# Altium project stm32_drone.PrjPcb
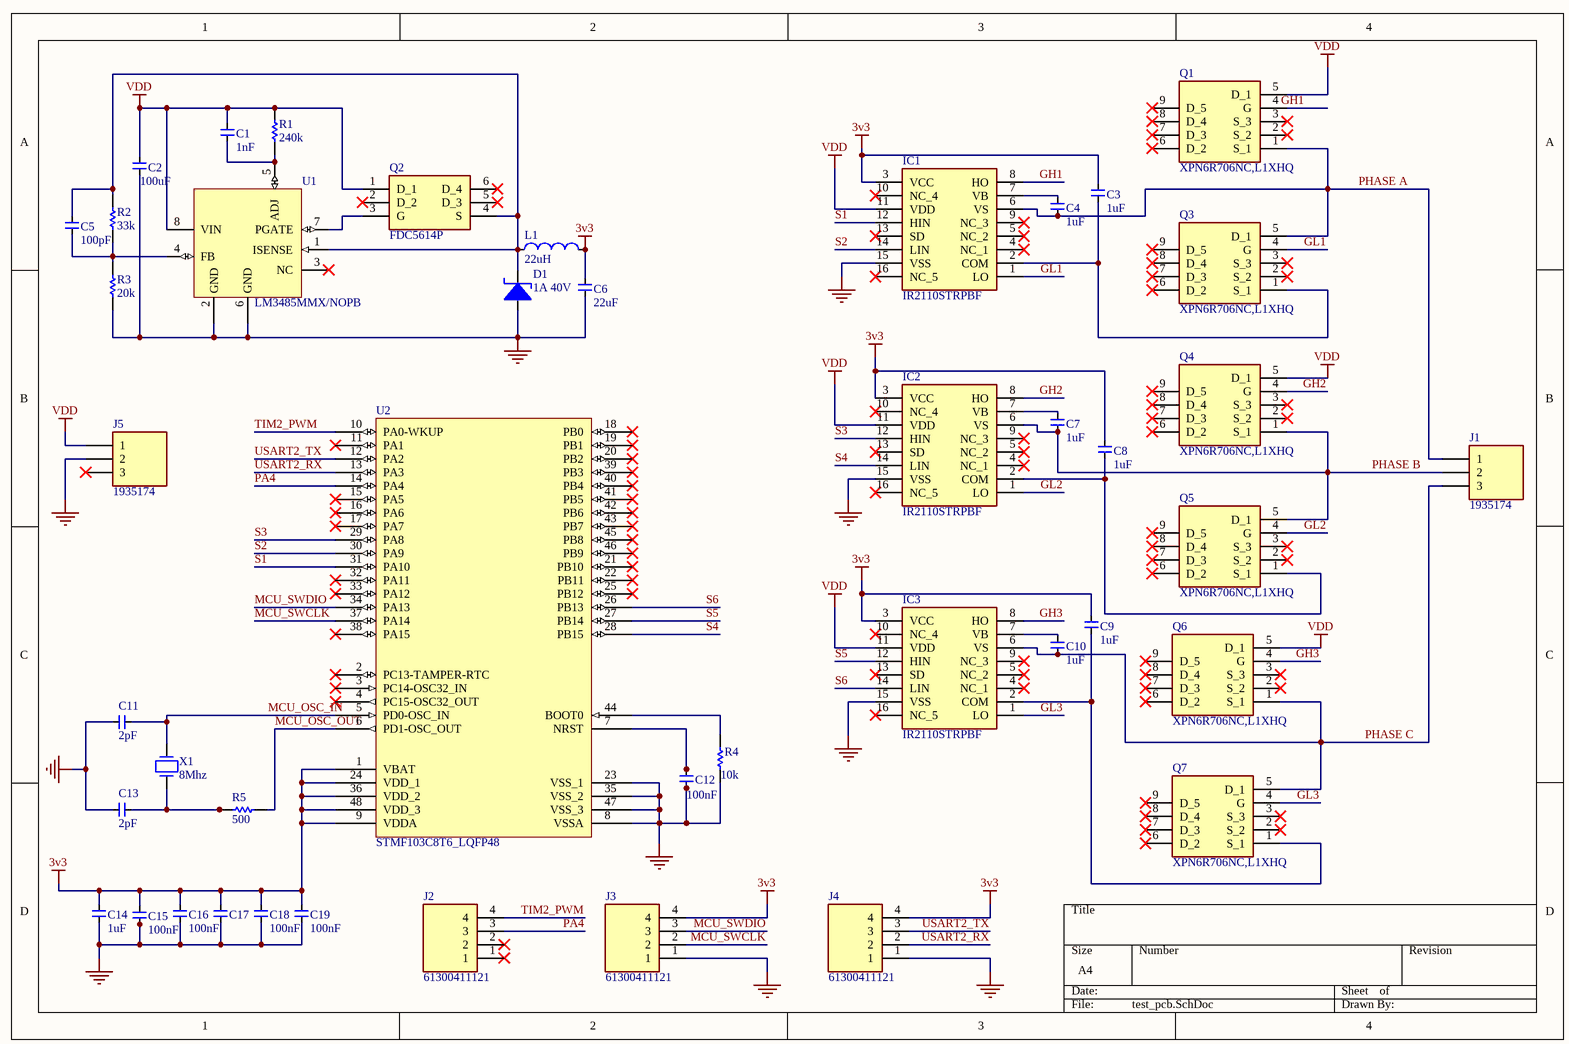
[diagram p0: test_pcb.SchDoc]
1 sheet, 44 parts. Net scope: global (net labels, ports and power ports of the same name join across sheets).
Board file: stm32_drone.PcbDoc

## Sheet test_pcb.SchDoc
size A4; SheetNumber: 1; SheetTotal: 1

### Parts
C1  1nF  [C0402C104J4RACTU]
C2  100uF  [GRM31x]
C3  1uF  [CAPC1608X90N]
C4  1uF  [GRM033D70J224ME01D]
C5  100pF  [CAPC0603X33N]
C6  22uF  [CAPC2012X145N]
C7  1uF  [GRM033D70J224ME01D]
C8  1uF  [GRM033D70J224ME01D]
C9  1uF  [GRM033D70J224ME01D]
C10  1uF  [GRM033D70J224ME01D]
C11  2pF  [GJM033]
C12  100nF  [GRM033D70J224ME01D]
C13  2pF  [GJM033]
C14  1uF  [CAPC1608X90N]
C15  100nF  [GRM033D70J224ME01D]
C16  100nF  [GRM033D70J224ME01D]
C17  (no value)  [GRM033D70J224ME01D]
C18  100nF  [GRM033D70J224ME01D]
C19  100nF  [GRM033D70J224ME01D]
D1  1A 40V  [DIOM5026X262N]
IC1  IR2110STRPBF  [SOIC127P1032X265-16N]
IC2  IR2110STRPBF  [SOIC127P1032X265-16N]
IC3  IR2110STRPBF  [SOIC127P1032X265-16N]
J1  1935174  [1935174]
J2  61300411121  [HDRV4W95P0X254_1X4_1016X254X854P]
J3  61300411121  [HDRV4W95P0X254_1X4_1016X254X854P]
J4  61300411121  [HDRV4W95P0X254_1X4_1016X254X854P]
J5  1935174  [1935174]
L1  22uH  [INDPM7166X300N]
Q1  XPN6R706NC,L1XHQ  [XPN6R706NCL1XHQ]
Q2  FDC5614P  [SOT95P280X110-6N]
Q3  XPN6R706NC,L1XHQ  [XPN6R706NCL1XHQ]
Q4  XPN6R706NC,L1XHQ  [XPN6R706NCL1XHQ]
Q5  XPN6R706NC,L1XHQ  [XPN6R706NCL1XHQ]
Q6  XPN6R706NC,L1XHQ  [XPN6R706NCL1XHQ]
Q7  XPN6R706NC,L1XHQ  [XPN6R706NCL1XHQ]
R1  240k  [ERJ3EKF1000V]
R2  33k  [ERA3AEB101V]
R3  20k  [ERJ2RKD1004X]
R4  10k  [RESC3115X60N]
R5  500  [ERA2AED122X]
U1  LM3485MMX/NOPB  [SOP65P490X110-8N]
U2  STMF103C8T6_LQFP48  [STM32F103C8T6_LQFP48]
X1  8Mhz  [8Mhz Crystal]

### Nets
3v3: C3.2 C6.2 C8.2 C9.2 C14.2 C15.2 C16.2 C17.2 C18.2 C19.2 IC1.3(VCC) IC2.3(VCC) IC3.3(VCC) J3.4 J4.4 L1.2 U2.1(VBAT) U2.9(VDDA) U2.24(VDD_1) U2.36(VDD_2) U2.48(VDD_3)
GND: C2.1 C6.1 C11.1 C12.1 C13.1 C14.1 C15.1 C16.1 C17.1 C18.1 C19.1 D1.+ IC1.15(VSS) IC2.15(VSS) IC3.15(VSS) J3.1 J4.1 J5.2 R3.4 R4.4 U1.2(GND) U1.6(GND) U2.8(VSSA) U2.23(VSS_1) U2.35(VSS_2) U2.47(VSS_3)
VDD: C1.2 C2.2 IC1.11(VDD) IC2.11(VDD) IC3.11(VDD) J5.1 Q1.5(D_1) Q2.1(D_1) Q4.5(D_1) Q6.5(D_1) R1.2 U1.8(VIN)
GH1: IC1.8(HO) Q1.4(G)
GH2: IC2.8(HO) Q4.4(G)
GH3: IC3.8(HO) Q6.4(G)
GL1: IC1.1(LO) Q3.4(G)
GL2: IC2.1(LO) Q5.4(G)
GL3: IC3.1(LO) Q7.4(G)
MCU_OSC_IN: C11.2 U2.5(PD0-OSC_IN) X1.2
MCU_OSC_OUT: R5.2 U2.6(PD1-OSC_OUT)
MCU_SWCLK: J3.2 U2.37(PA14)
MCU_SWDIO: J3.3 U2.34(PA13)
PA4: J2.3 U2.14(PA4)
PHASE A: C4.1 IC1.6(VS) J1.1 Q1.1(S_1) Q3.5(D_1)
PHASE B: C7.1 IC2.6(VS) J1.2 Q4.1(S_1) Q5.5(D_1)
PHASE C: C10.1 IC3.6(VS) J1.3 Q6.1(S_1) Q7.5(D_1)
S1: IC1.12(HIN) U2.31(PA10)
S2: IC1.14(LIN) U2.30(PA9)
S3: IC2.12(HIN) U2.29(PA8)
S4: IC2.14(LIN) U2.28(PB15)
S5: IC3.12(HIN) U2.27(PB14)
S6: IC3.14(LIN) U2.26(PB13)
TIM2_PWM: J2.4 U2.10(PA0-WKUP)
USART2_RX: J4.2 U2.13(PA3)
USART2_TX: J4.3 U2.12(PA2)
NetC1_1: C1.1 R1.4 U1.5(ADJ)
NetC3_1: C3.1 IC1.2(COM) Q3.1(S_1)
NetC4_2: C4.2 IC1.7(VB)
NetC5_1: C5.1 R2.4 R3.2 U1.4(FB)
NetC5_2: C5.2 D1.- L1.1 Q2.4(S) R2.2 U1.1(ISENSE)
NetC7_2: C7.2 IC2.7(VB)
NetC8_1: C8.1 IC2.2(COM) Q5.1(S_1)
NetC9_1: C9.1 IC3.2(COM) Q7.1(S_1)
NetC10_2: C10.2 IC3.7(VB)
NetC12_2: C12.2 U2.7(NRST)
NetC13_2: C13.2 R5.4 X1.1
NetQ2_3: Q2.3(G) U1.7(PGATE)
NetR4_2: R4.2 U2.44(BOOT0)

Not connected (* = marked no-connect by the designer): IC1 4(NC_1)* 5(NC_2)* 9(NC_3)* 10(NC_4)* 13(SD)* 16(NC_5)*; IC2 4(NC_1)* 5(NC_2)* 9(NC_3)* 10(NC_4)* 13(SD)* 16(NC_5)*; IC3 4(NC_1)* 5(NC_2)* 9(NC_3)* 10(NC_4)* 13(SD)* 16(NC_5)*; J2 1* 2*; J5 3*; Q1 2(S_2)* 3(S_3)* 6(D_2)* 7(D_3)* 8(D_4)* 9(D_5)*; Q2 2(D_2)* 5(D_3)* 6(D_4)*; Q3 2(S_2)* 3(S_3)* 6(D_2)* 7(D_3)* 8(D_4)* 9(D_5)*; Q4 2(S_2)* 3(S_3)* 6(D_2)* 7(D_3)* 8(D_4)* 9(D_5)*; Q5 2(S_2)* 3(S_3)* 6(D_2)* 7(D_3)* 8(D_4)* 9(D_5)*; Q6 2(S_2)* 3(S_3)* 6(D_2)* 7(D_3)* 8(D_4)* 9(D_5)*; Q7 2(S_2)* 3(S_3)* 6(D_2)* 7(D_3)* 8(D_4)* 9(D_5)*; U1 3(NC)*; U2 2(PC13-TAMPER-RTC)* 3(PC14-OSC32_IN)* 4(PC15-OSC32_OUT)* 11(PA1)* 15(PA5)* 16(PA6)* 17(PA7)* 18(PB0)* 19(PB1)* 20(PB2)* 21(PB10)* 22(PB11)* 25(PB12)* 32(PA11)* 33(PA12)* 38(PA15)* 39(PB3)* 40(PB4)* 41(PB5)* 42(PB6)* 43(PB7)* 45(PB8)* 46(PB9)*

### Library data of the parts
C1 = C0402C102J5GECTU: Ceramic Capacitor, Multilayer, Ceramic, 50V, 5% +Tol, 5% -Tol, C0G, -/+30ppm/Cel TC, 0.001uF, Surface Mount, 0402; Manufacturer: KEMET
C2 = GRM31CR60J107MEA8K: Ceramic Capacitor, Multilayer, Ceramic, 6.3V, 20% +Tol, 20% -Tol, X5R, 15% TC, 100uF, Surface Mount, 1206; Manufacturer: Murata
C3 C14 = CC0603KRX5R8BB105: Ceramic Capacitor, Multilayer, Ceramic, 25V, 10% +Tol, 10% -Tol, X5R, 15% TC, 1uF, Surface Mount, 0603; Manufacturer: Yageo; Multilayer: Yes
C4 C7-C10 = GRM033R60J105MEA2D: Ceramic Capacitor, Multilayer, Ceramic, 6.3V, 20% +Tol, 20% -Tol, X5R, 15% TC, 1uF, Surface Mount, 0201; Manufacturer: Murata; Multilayer: Yes
C5 = GRM0335C1H101JA01D: Ceramic Capacitor, Multilayer, Ceramic, 50V, 5% +Tol, 5% -Tol, C0G, 30ppm/Cel TC, 0.0001uF, Surface Mount, 0201; Manufacturer: Murata; Multilayer: Yes
C6 = C2012X5R1V226M125AC: Ceramic Capacitor, Multilayer, Ceramic, 35V, 20% +Tol, 20% -Tol, X5R, 15% TC, 22uF, Surface Mount, 0805; Manufacturer: TDK; Multilayer: Yes
C11 C13 = GJM0335C1E2R0BB01D: Ceramic Capacitor, Multilayer, Ceramic, 25V, 5% +Tol, 5% -Tol, C0G, 30ppm/Cel TC, 0.000002uF, Surface Mount, 0201; Manufacturer: Murata; Multilayer: Yes
C12 C15 C16 C18 C19 = GRM033C80J104KE15D: Ceramic Capacitor, Multilayer, Ceramic, 6.3V, 10% +Tol, 10% -Tol, X6S, 22% TC, 0.1uF, Surface Mount, 0201; Manufacturer: Murata; Multilayer: Yes
C17 = GRM033C80J104KE15D: Ceramic Capacitor, Multilayer, Ceramic, 6.3V, 10% +Tol, 10% -Tol, X6S, 22% TC, 0.1uF, Surface Mount, 0201; Manufacturer: Murata; Value: 100nF; Multilayer: Yes
D1 = SS14: Rectifier Diode, Schottky, 1 Phase, 1 Element, 1A, 40V V(RRM), Silicon, DO-214AC; Manufacturer: ON Semiconductor / Fairchild; Package Body Material: Plastic; Forward Voltage: 500mV; Non-rep Pk Forward Current-Max: 30A; Number of Elements: 1; Additional Feature: FREE WHEELING DIODE; Max Power Dissipation: 1.1W; Qualification Status: Not Qualified
IC1-IC3 = IR2110STRPBF: Half Bridge Based MOSFET Driver, 2.5A, CMOS, PDSO16; Manufacturer: Infineon; Package Body Material: Plastic; High Side Driver: Yes; Channels: 1; Supply Voltage1-Max: 520V; Supply Voltage1-Min: 6V; Max Supply Voltage: 20V; Min Supply Voltage: 3.3V; Nominal Supply Voltage: 15V; Turn-Off Delay Time: 0.125us; Turn-On Delay Time: 0.15us; Package Equivalence Code: SOP16,.4; Time @ Peak Reflow Temperature-Max (s): 30s; Qualification Status: Not Qualified
J1 J5 = 1935174: Barrier Strip Terminal Block, 17.5A, 1.5mm2, 1 Row(s), 1 Deck(s); Manufacturer: Phoenix Contact; Fastening Method: SCREW; Number of Decks: 1; Number of Ways: 3; Voltage Rating: 250V; Wire/Cable Gauge: 14AWG; Safety Approval: UL
L1 = ECS-MPIL0630-220MC: General Purpose Inductor, 22uH, 20%, 1 Element, Ferrite-Core, SMD, 2826; Manufacturer: ECS International
Q1 Q3-Q7 = XPN6R706NC,L1XHQ: Mosfet N-ch 60V 40A 8TSON; Manufacturer: Toshiba
Q2 = FDC5614P: Small Signal Field-Effect Transistor, 3A I(D), 60V, 1-Element, P-Channel, Silicon, Metal-oxide Semiconductor FET; Manufacturer: ON Semiconductor / Fairchild; Package Body Material: Plastic; Drain-source On Resistance-Max: 105mR; Number of Elements: 1; Operating Mode: ENHANCEMENT MODE; Power Dissipation-Max (Abs): 1.6W; Transistor Application: SWITCHING; Qualification Status: Not Qualified
R1 = ERJ-3GEYJ244V: Fixed Resistor, Metal Glaze/thick Film, 0.1W, 240000ohm, 75V, 5% +/-Tol, 200ppm/Cel, Surface Mount, 0603; Manufacturer: Panasonic; Power: 100mW; Rated Temperature: 70°C; Value: 240kR; Temperature Coefficient (ppm/Cel): 200; Package Height: 0.45mm; Package Length: 1.6mm; Package Width: 0.8mm; Reference Standard: AEC-Q200
R2 = ERA-3AEB333V: Fixed Resistor, Thin Film, 0.1W, 33000ohm, 75V, 0.1% +/-Tol, 25ppm/Cel, Surface Mount, 0603; Manufacturer: Panasonic; Power: 100mW; Rated Temperature: 85°C; Value: 33kR; Temperature Coefficient (ppm/Cel): 25; Package Height: 0.45mm; Package Length: 1.6mm; Package Width: 0.8mm; Reference Standard: AEC-Q200
R3 = ERJ-2RKF2002X: Fixed Resistor, Metal Glaze/thick Film, 0.1W, 20000ohm, 50V, 1% +/-Tol, 100ppm/Cel, Surface Mount, 0402; Manufacturer: Panasonic; Power: 100mW; Rated Temperature: 70°C; Value: 20kR; Temperature Coefficient (ppm/Cel): 100; Package Height: 0.35mm; Package Length: 1mm; Package Width: 0.5mm; Reference Standard: AEC-Q200
R4 = RNCP1206FTD10K0: Fixed Resistor, Thin Film, 0.5W, 10000ohm, 200V, 1% +/-Tol, 100ppm/Cel, Surface Mount, 1206; Manufacturer: Stackpole Electronics; Additional Feature: ANTI-SULFUR; Power: 500mW; Rated Temperature: 70°C; Value: 10kR; Temperature Coefficient (ppm/Cel): 100; Package Height: 0.5mm; Package Length: 3.1mm; Package Width: 1.5mm
R5 = ERA-2AEB4990X: Fixed Resistor, Thin Film, 0.063W, 499ohm, 50V, 0.1% +/-Tol, 25ppm/Cel, Surface Mount, 0402; Manufacturer: Panasonic; Power: 63mW; Rated Temperature: 85°C; Value: 499R; Working Voltage: 25V; Temperature Coefficient (ppm/Cel): 25; Package Height: 0.35mm; Package Length: 1mm; Package Width: 0.5mm; Reference Standard: AEC-Q200
U1 = LM3485MMX/NOPB: Switching Controller, Voltage-mode, 0.1A, 1000kHz Switching Freq-Max, PDSO8; Manufacturer: TI National Semiconductor; Package Body Material: Plastic; Control Technique: HYSTERETIC CURRENT MODE; Max Supply Voltage: 35V; Min Input Voltage: 4.5V; Nominal Supply Voltage: 12V; Channels: 1; Max Output current: 100mA; Package Equivalence Code: TSSOP8,.19; Switcher Configuration: SINGLE; Frequency: 1MHz; Time @ Peak Reflow Temperature-Max (s): 40s; Qualification Status: Not Qualified
U2 = STM32F103C8T6: ARM Cortex-M3 STM32 F1 Microcontroller 32-Bit 72MHz 64kB FLASH LQFP48 STM32F103C8T6; Manufacturer: STMicroelectronics; Package Body Material: Plastic; Clock Frequency: 16MHz; Number of I/O Lines: 37; Package Equivalence Code: QFP48,.35SQ,20; Power Supplies: 2.5/3.3; Max Supply Current: 50mA; Max Supply Voltage: 3.6V; Min Supply Voltage: 2V; Nominal Supply Voltage: 3.3V; Time @ Peak Reflow Temperature-Max (s): 30s; Peripherals: POR; Interface: I2C; Qualification Status: Not Qualified
X1 = H130A-8.000-8-2030-TR: Parallel - Fundamental Quartz Crystal, 8MHz Min, 150MHz Max, 8MHz Nom; Manufacturer: Raltron Electronics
